VERSION 5.7 ;
  NOWIREEXTENSIONATPIN ON ;
  DIVIDERCHAR "/" ;
  BUSBITCHARS "[]" ;
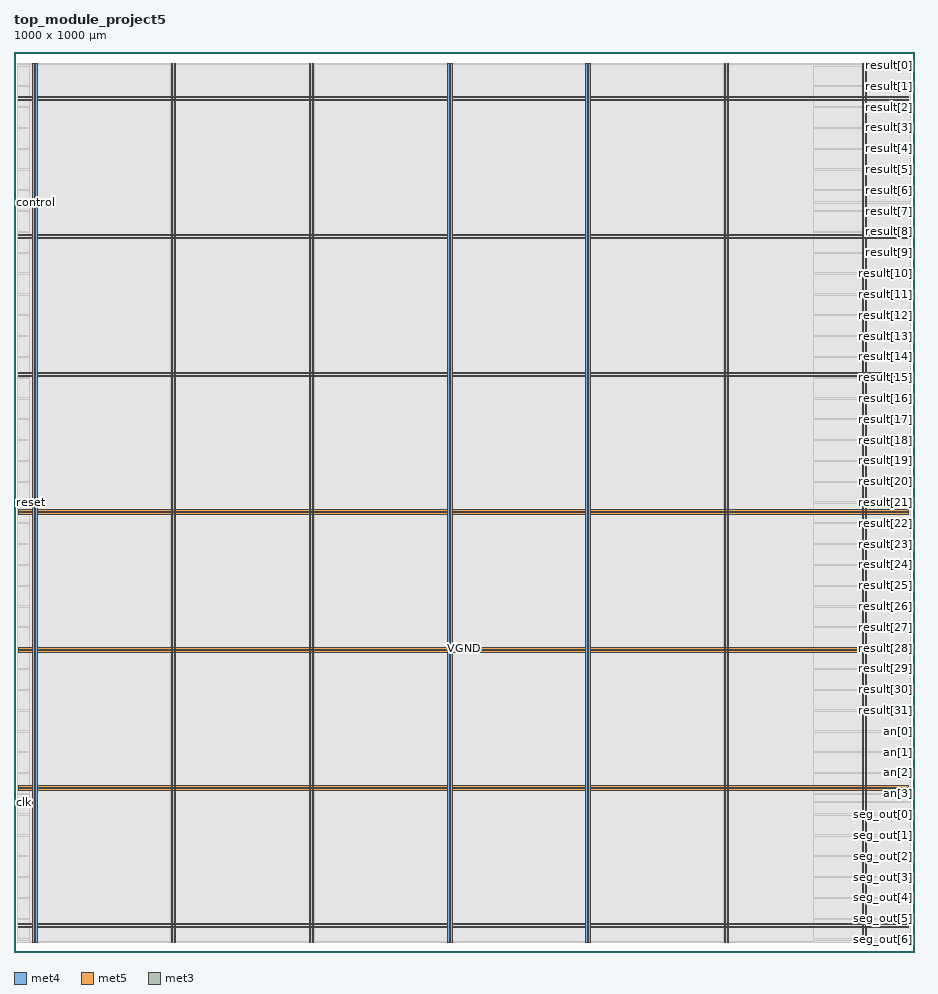
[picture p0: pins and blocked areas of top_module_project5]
MACRO top_module_project5
  CLASS BLOCK ;
  FOREIGN top_module_project5 ;
  ORIGIN 0.000 0.000 ;
  SIZE 1000.000 BY 1000.000 ;
  PIN VGND
    DIRECTION INOUT ;
    USE GROUND ;
    PORT
      LAYER met4 ;
        RECT 24.340 10.640 25.940 987.600 ;
    END
    PORT
      LAYER met4 ;
        RECT 177.940 10.640 179.540 987.600 ;
    END
    PORT
      LAYER met4 ;
        RECT 331.540 10.640 333.140 987.600 ;
    END
    PORT
      LAYER met4 ;
        RECT 485.140 10.640 486.740 987.600 ;
    END
    PORT
      LAYER met4 ;
        RECT 638.740 10.640 640.340 987.600 ;
    END
    PORT
      LAYER met4 ;
        RECT 792.340 10.640 793.940 987.600 ;
    END
    PORT
      LAYER met4 ;
        RECT 945.940 10.640 947.540 987.600 ;
    END
    PORT
      LAYER met5 ;
        RECT 5.280 30.030 994.300 31.630 ;
    END
    PORT
      LAYER met5 ;
        RECT 5.280 183.210 994.300 184.810 ;
    END
    PORT
      LAYER met5 ;
        RECT 5.280 336.390 994.300 337.990 ;
    END
    PORT
      LAYER met5 ;
        RECT 5.280 489.570 994.300 491.170 ;
    END
    PORT
      LAYER met5 ;
        RECT 5.280 642.750 994.300 644.350 ;
    END
    PORT
      LAYER met5 ;
        RECT 5.280 795.930 994.300 797.530 ;
    END
    PORT
      LAYER met5 ;
        RECT 5.280 949.110 994.300 950.710 ;
    END
  END VGND
  PIN VPWR
    DIRECTION INOUT ;
    USE POWER ;
    PORT
      LAYER met4 ;
        RECT 21.040 10.640 22.640 987.600 ;
    END
    PORT
      LAYER met4 ;
        RECT 174.640 10.640 176.240 987.600 ;
    END
    PORT
      LAYER met4 ;
        RECT 328.240 10.640 329.840 987.600 ;
    END
    PORT
      LAYER met4 ;
        RECT 481.840 10.640 483.440 987.600 ;
    END
    PORT
      LAYER met4 ;
        RECT 635.440 10.640 637.040 987.600 ;
    END
    PORT
      LAYER met4 ;
        RECT 789.040 10.640 790.640 987.600 ;
    END
    PORT
      LAYER met4 ;
        RECT 942.640 10.640 944.240 987.600 ;
    END
    PORT
      LAYER met5 ;
        RECT 5.280 26.730 994.300 28.330 ;
    END
    PORT
      LAYER met5 ;
        RECT 5.280 179.910 994.300 181.510 ;
    END
    PORT
      LAYER met5 ;
        RECT 5.280 333.090 994.300 334.690 ;
    END
    PORT
      LAYER met5 ;
        RECT 5.280 486.270 994.300 487.870 ;
    END
    PORT
      LAYER met5 ;
        RECT 5.280 639.450 994.300 641.050 ;
    END
    PORT
      LAYER met5 ;
        RECT 5.280 792.630 994.300 794.230 ;
    END
    PORT
      LAYER met5 ;
        RECT 5.280 945.810 994.300 947.410 ;
    END
  END VPWR
  PIN an[0]
    DIRECTION OUTPUT ;
    USE SIGNAL ;
    ANTENNADIFFAREA 0.445500 ;
    PORT
      LAYER met3 ;
        RECT 996.000 244.840 1000.000 245.440 ;
    END
  END an[0]
  PIN an[1]
    DIRECTION OUTPUT ;
    USE SIGNAL ;
    ANTENNADIFFAREA 0.445500 ;
    PORT
      LAYER met3 ;
        RECT 996.000 221.720 1000.000 222.320 ;
    END
  END an[1]
  PIN an[2]
    DIRECTION OUTPUT ;
    USE SIGNAL ;
    ANTENNADIFFAREA 0.445500 ;
    PORT
      LAYER met3 ;
        RECT 996.000 198.600 1000.000 199.200 ;
    END
  END an[2]
  PIN an[3]
    DIRECTION OUTPUT ;
    USE SIGNAL ;
    ANTENNADIFFAREA 0.445500 ;
    PORT
      LAYER met3 ;
        RECT 996.000 175.480 1000.000 176.080 ;
    END
  END an[3]
  PIN clk
    DIRECTION INPUT ;
    USE SIGNAL ;
    ANTENNAGATEAREA 0.852000 ;
    PORT
      LAYER met3 ;
        RECT 0.000 165.960 4.000 166.560 ;
    END
  END clk
  PIN control
    DIRECTION INPUT ;
    USE SIGNAL ;
    ANTENNAGATEAREA 0.990000 ;
    PORT
      LAYER met3 ;
        RECT 0.000 832.360 4.000 832.960 ;
    END
  END control
  PIN reset
    DIRECTION INPUT ;
    USE SIGNAL ;
    ANTENNAGATEAREA 0.742500 ;
    PORT
      LAYER met3 ;
        RECT 0.000 499.160 4.000 499.760 ;
    END
  END reset
  PIN result[0]
    DIRECTION OUTPUT ;
    USE SIGNAL ;
    ANTENNADIFFAREA 0.445500 ;
    PORT
      LAYER met3 ;
        RECT 996.000 984.680 1000.000 985.280 ;
    END
  END result[0]
  PIN result[10]
    DIRECTION OUTPUT ;
    USE SIGNAL ;
    ANTENNADIFFAREA 0.445500 ;
    PORT
      LAYER met3 ;
        RECT 996.000 753.480 1000.000 754.080 ;
    END
  END result[10]
  PIN result[11]
    DIRECTION OUTPUT ;
    USE SIGNAL ;
    ANTENNADIFFAREA 0.445500 ;
    PORT
      LAYER met3 ;
        RECT 996.000 730.360 1000.000 730.960 ;
    END
  END result[11]
  PIN result[12]
    DIRECTION OUTPUT ;
    USE SIGNAL ;
    ANTENNADIFFAREA 0.445500 ;
    PORT
      LAYER met3 ;
        RECT 996.000 707.240 1000.000 707.840 ;
    END
  END result[12]
  PIN result[13]
    DIRECTION OUTPUT ;
    USE SIGNAL ;
    ANTENNADIFFAREA 0.445500 ;
    PORT
      LAYER met3 ;
        RECT 996.000 684.120 1000.000 684.720 ;
    END
  END result[13]
  PIN result[14]
    DIRECTION OUTPUT ;
    USE SIGNAL ;
    ANTENNADIFFAREA 0.445500 ;
    PORT
      LAYER met3 ;
        RECT 996.000 661.000 1000.000 661.600 ;
    END
  END result[14]
  PIN result[15]
    DIRECTION OUTPUT ;
    USE SIGNAL ;
    ANTENNADIFFAREA 0.445500 ;
    PORT
      LAYER met3 ;
        RECT 996.000 637.880 1000.000 638.480 ;
    END
  END result[15]
  PIN result[16]
    DIRECTION OUTPUT ;
    USE SIGNAL ;
    ANTENNADIFFAREA 0.445500 ;
    PORT
      LAYER met3 ;
        RECT 996.000 614.760 1000.000 615.360 ;
    END
  END result[16]
  PIN result[17]
    DIRECTION OUTPUT ;
    USE SIGNAL ;
    ANTENNADIFFAREA 0.445500 ;
    PORT
      LAYER met3 ;
        RECT 996.000 591.640 1000.000 592.240 ;
    END
  END result[17]
  PIN result[18]
    DIRECTION OUTPUT ;
    USE SIGNAL ;
    ANTENNADIFFAREA 0.445500 ;
    PORT
      LAYER met3 ;
        RECT 996.000 568.520 1000.000 569.120 ;
    END
  END result[18]
  PIN result[19]
    DIRECTION OUTPUT ;
    USE SIGNAL ;
    ANTENNADIFFAREA 0.445500 ;
    PORT
      LAYER met3 ;
        RECT 996.000 545.400 1000.000 546.000 ;
    END
  END result[19]
  PIN result[1]
    DIRECTION OUTPUT ;
    USE SIGNAL ;
    ANTENNADIFFAREA 0.445500 ;
    PORT
      LAYER met3 ;
        RECT 996.000 961.560 1000.000 962.160 ;
    END
  END result[1]
  PIN result[20]
    DIRECTION OUTPUT ;
    USE SIGNAL ;
    ANTENNADIFFAREA 0.445500 ;
    PORT
      LAYER met3 ;
        RECT 996.000 522.280 1000.000 522.880 ;
    END
  END result[20]
  PIN result[21]
    DIRECTION OUTPUT ;
    USE SIGNAL ;
    ANTENNADIFFAREA 0.445500 ;
    PORT
      LAYER met3 ;
        RECT 996.000 499.160 1000.000 499.760 ;
    END
  END result[21]
  PIN result[22]
    DIRECTION OUTPUT ;
    USE SIGNAL ;
    ANTENNADIFFAREA 0.445500 ;
    PORT
      LAYER met3 ;
        RECT 996.000 476.040 1000.000 476.640 ;
    END
  END result[22]
  PIN result[23]
    DIRECTION OUTPUT ;
    USE SIGNAL ;
    ANTENNADIFFAREA 0.445500 ;
    PORT
      LAYER met3 ;
        RECT 996.000 452.920 1000.000 453.520 ;
    END
  END result[23]
  PIN result[24]
    DIRECTION OUTPUT ;
    USE SIGNAL ;
    ANTENNADIFFAREA 0.445500 ;
    PORT
      LAYER met3 ;
        RECT 996.000 429.800 1000.000 430.400 ;
    END
  END result[24]
  PIN result[25]
    DIRECTION OUTPUT ;
    USE SIGNAL ;
    ANTENNADIFFAREA 0.445500 ;
    PORT
      LAYER met3 ;
        RECT 996.000 406.680 1000.000 407.280 ;
    END
  END result[25]
  PIN result[26]
    DIRECTION OUTPUT ;
    USE SIGNAL ;
    ANTENNADIFFAREA 0.445500 ;
    PORT
      LAYER met3 ;
        RECT 996.000 383.560 1000.000 384.160 ;
    END
  END result[26]
  PIN result[27]
    DIRECTION OUTPUT ;
    USE SIGNAL ;
    ANTENNADIFFAREA 0.445500 ;
    PORT
      LAYER met3 ;
        RECT 996.000 360.440 1000.000 361.040 ;
    END
  END result[27]
  PIN result[28]
    DIRECTION OUTPUT ;
    USE SIGNAL ;
    ANTENNADIFFAREA 0.445500 ;
    PORT
      LAYER met3 ;
        RECT 996.000 337.320 1000.000 337.920 ;
    END
  END result[28]
  PIN result[29]
    DIRECTION OUTPUT ;
    USE SIGNAL ;
    ANTENNADIFFAREA 0.445500 ;
    PORT
      LAYER met3 ;
        RECT 996.000 314.200 1000.000 314.800 ;
    END
  END result[29]
  PIN result[2]
    DIRECTION OUTPUT ;
    USE SIGNAL ;
    ANTENNADIFFAREA 0.445500 ;
    PORT
      LAYER met3 ;
        RECT 996.000 938.440 1000.000 939.040 ;
    END
  END result[2]
  PIN result[30]
    DIRECTION OUTPUT ;
    USE SIGNAL ;
    ANTENNADIFFAREA 0.445500 ;
    PORT
      LAYER met3 ;
        RECT 996.000 291.080 1000.000 291.680 ;
    END
  END result[30]
  PIN result[31]
    DIRECTION OUTPUT ;
    USE SIGNAL ;
    ANTENNADIFFAREA 0.445500 ;
    PORT
      LAYER met3 ;
        RECT 996.000 267.960 1000.000 268.560 ;
    END
  END result[31]
  PIN result[3]
    DIRECTION OUTPUT ;
    USE SIGNAL ;
    ANTENNADIFFAREA 0.445500 ;
    PORT
      LAYER met3 ;
        RECT 996.000 915.320 1000.000 915.920 ;
    END
  END result[3]
  PIN result[4]
    DIRECTION OUTPUT ;
    USE SIGNAL ;
    ANTENNADIFFAREA 0.445500 ;
    PORT
      LAYER met3 ;
        RECT 996.000 892.200 1000.000 892.800 ;
    END
  END result[4]
  PIN result[5]
    DIRECTION OUTPUT ;
    USE SIGNAL ;
    ANTENNADIFFAREA 0.445500 ;
    PORT
      LAYER met3 ;
        RECT 996.000 869.080 1000.000 869.680 ;
    END
  END result[5]
  PIN result[6]
    DIRECTION OUTPUT ;
    USE SIGNAL ;
    ANTENNADIFFAREA 0.445500 ;
    PORT
      LAYER met3 ;
        RECT 996.000 845.960 1000.000 846.560 ;
    END
  END result[6]
  PIN result[7]
    DIRECTION OUTPUT ;
    USE SIGNAL ;
    ANTENNADIFFAREA 0.445500 ;
    PORT
      LAYER met3 ;
        RECT 996.000 822.840 1000.000 823.440 ;
    END
  END result[7]
  PIN result[8]
    DIRECTION OUTPUT ;
    USE SIGNAL ;
    ANTENNADIFFAREA 0.445500 ;
    PORT
      LAYER met3 ;
        RECT 996.000 799.720 1000.000 800.320 ;
    END
  END result[8]
  PIN result[9]
    DIRECTION OUTPUT ;
    USE SIGNAL ;
    ANTENNADIFFAREA 0.445500 ;
    PORT
      LAYER met3 ;
        RECT 996.000 776.600 1000.000 777.200 ;
    END
  END result[9]
  PIN seg_out[0]
    DIRECTION OUTPUT ;
    USE SIGNAL ;
    ANTENNADIFFAREA 0.445500 ;
    PORT
      LAYER met3 ;
        RECT 996.000 152.360 1000.000 152.960 ;
    END
  END seg_out[0]
  PIN seg_out[1]
    DIRECTION OUTPUT ;
    USE SIGNAL ;
    ANTENNADIFFAREA 0.445500 ;
    PORT
      LAYER met3 ;
        RECT 996.000 129.240 1000.000 129.840 ;
    END
  END seg_out[1]
  PIN seg_out[2]
    DIRECTION OUTPUT ;
    USE SIGNAL ;
    ANTENNADIFFAREA 0.445500 ;
    PORT
      LAYER met3 ;
        RECT 996.000 106.120 1000.000 106.720 ;
    END
  END seg_out[2]
  PIN seg_out[3]
    DIRECTION OUTPUT ;
    USE SIGNAL ;
    ANTENNADIFFAREA 0.445500 ;
    PORT
      LAYER met3 ;
        RECT 996.000 83.000 1000.000 83.600 ;
    END
  END seg_out[3]
  PIN seg_out[4]
    DIRECTION OUTPUT ;
    USE SIGNAL ;
    ANTENNADIFFAREA 0.445500 ;
    PORT
      LAYER met3 ;
        RECT 996.000 59.880 1000.000 60.480 ;
    END
  END seg_out[4]
  PIN seg_out[5]
    DIRECTION OUTPUT ;
    USE SIGNAL ;
    ANTENNADIFFAREA 0.445500 ;
    PORT
      LAYER met3 ;
        RECT 996.000 36.760 1000.000 37.360 ;
    END
  END seg_out[5]
  PIN seg_out[6]
    DIRECTION OUTPUT ;
    USE SIGNAL ;
    ANTENNADIFFAREA 0.445500 ;
    PORT
      LAYER met3 ;
        RECT 996.000 13.640 1000.000 14.240 ;
    END
  END seg_out[6]
  OBS
      LAYER nwell ;
        RECT 5.330 10.795 994.250 987.550 ;
      LAYER li1 ;
        RECT 5.520 10.795 994.060 987.445 ;
      LAYER met1 ;
        RECT 4.210 10.640 994.060 987.600 ;
      LAYER met2 ;
        RECT 4.230 10.695 992.130 987.545 ;
      LAYER met3 ;
        RECT 3.990 985.680 996.000 987.525 ;
        RECT 3.990 984.280 995.600 985.680 ;
        RECT 3.990 962.560 996.000 984.280 ;
        RECT 3.990 961.160 995.600 962.560 ;
        RECT 3.990 939.440 996.000 961.160 ;
        RECT 3.990 938.040 995.600 939.440 ;
        RECT 3.990 916.320 996.000 938.040 ;
        RECT 3.990 914.920 995.600 916.320 ;
        RECT 3.990 893.200 996.000 914.920 ;
        RECT 3.990 891.800 995.600 893.200 ;
        RECT 3.990 870.080 996.000 891.800 ;
        RECT 3.990 868.680 995.600 870.080 ;
        RECT 3.990 846.960 996.000 868.680 ;
        RECT 3.990 845.560 995.600 846.960 ;
        RECT 3.990 833.360 996.000 845.560 ;
        RECT 4.400 831.960 996.000 833.360 ;
        RECT 3.990 823.840 996.000 831.960 ;
        RECT 3.990 822.440 995.600 823.840 ;
        RECT 3.990 800.720 996.000 822.440 ;
        RECT 3.990 799.320 995.600 800.720 ;
        RECT 3.990 777.600 996.000 799.320 ;
        RECT 3.990 776.200 995.600 777.600 ;
        RECT 3.990 754.480 996.000 776.200 ;
        RECT 3.990 753.080 995.600 754.480 ;
        RECT 3.990 731.360 996.000 753.080 ;
        RECT 3.990 729.960 995.600 731.360 ;
        RECT 3.990 708.240 996.000 729.960 ;
        RECT 3.990 706.840 995.600 708.240 ;
        RECT 3.990 685.120 996.000 706.840 ;
        RECT 3.990 683.720 995.600 685.120 ;
        RECT 3.990 662.000 996.000 683.720 ;
        RECT 3.990 660.600 995.600 662.000 ;
        RECT 3.990 638.880 996.000 660.600 ;
        RECT 3.990 637.480 995.600 638.880 ;
        RECT 3.990 615.760 996.000 637.480 ;
        RECT 3.990 614.360 995.600 615.760 ;
        RECT 3.990 592.640 996.000 614.360 ;
        RECT 3.990 591.240 995.600 592.640 ;
        RECT 3.990 569.520 996.000 591.240 ;
        RECT 3.990 568.120 995.600 569.520 ;
        RECT 3.990 546.400 996.000 568.120 ;
        RECT 3.990 545.000 995.600 546.400 ;
        RECT 3.990 523.280 996.000 545.000 ;
        RECT 3.990 521.880 995.600 523.280 ;
        RECT 3.990 500.160 996.000 521.880 ;
        RECT 4.400 498.760 995.600 500.160 ;
        RECT 3.990 477.040 996.000 498.760 ;
        RECT 3.990 475.640 995.600 477.040 ;
        RECT 3.990 453.920 996.000 475.640 ;
        RECT 3.990 452.520 995.600 453.920 ;
        RECT 3.990 430.800 996.000 452.520 ;
        RECT 3.990 429.400 995.600 430.800 ;
        RECT 3.990 407.680 996.000 429.400 ;
        RECT 3.990 406.280 995.600 407.680 ;
        RECT 3.990 384.560 996.000 406.280 ;
        RECT 3.990 383.160 995.600 384.560 ;
        RECT 3.990 361.440 996.000 383.160 ;
        RECT 3.990 360.040 995.600 361.440 ;
        RECT 3.990 338.320 996.000 360.040 ;
        RECT 3.990 336.920 995.600 338.320 ;
        RECT 3.990 315.200 996.000 336.920 ;
        RECT 3.990 313.800 995.600 315.200 ;
        RECT 3.990 292.080 996.000 313.800 ;
        RECT 3.990 290.680 995.600 292.080 ;
        RECT 3.990 268.960 996.000 290.680 ;
        RECT 3.990 267.560 995.600 268.960 ;
        RECT 3.990 245.840 996.000 267.560 ;
        RECT 3.990 244.440 995.600 245.840 ;
        RECT 3.990 222.720 996.000 244.440 ;
        RECT 3.990 221.320 995.600 222.720 ;
        RECT 3.990 199.600 996.000 221.320 ;
        RECT 3.990 198.200 995.600 199.600 ;
        RECT 3.990 176.480 996.000 198.200 ;
        RECT 3.990 175.080 995.600 176.480 ;
        RECT 3.990 166.960 996.000 175.080 ;
        RECT 4.400 165.560 996.000 166.960 ;
        RECT 3.990 153.360 996.000 165.560 ;
        RECT 3.990 151.960 995.600 153.360 ;
        RECT 3.990 130.240 996.000 151.960 ;
        RECT 3.990 128.840 995.600 130.240 ;
        RECT 3.990 107.120 996.000 128.840 ;
        RECT 3.990 105.720 995.600 107.120 ;
        RECT 3.990 84.000 996.000 105.720 ;
        RECT 3.990 82.600 995.600 84.000 ;
        RECT 3.990 60.880 996.000 82.600 ;
        RECT 3.990 59.480 995.600 60.880 ;
        RECT 3.990 37.760 996.000 59.480 ;
        RECT 3.990 36.360 995.600 37.760 ;
        RECT 3.990 14.640 996.000 36.360 ;
        RECT 3.990 13.240 995.600 14.640 ;
        RECT 3.990 10.715 996.000 13.240 ;
      LAYER met4 ;
        RECT 16.855 11.735 20.640 985.825 ;
        RECT 23.040 11.735 23.940 985.825 ;
        RECT 26.340 11.735 174.240 985.825 ;
        RECT 176.640 11.735 177.540 985.825 ;
        RECT 179.940 11.735 327.840 985.825 ;
        RECT 330.240 11.735 331.140 985.825 ;
        RECT 333.540 11.735 481.440 985.825 ;
        RECT 483.840 11.735 484.740 985.825 ;
        RECT 487.140 11.735 635.040 985.825 ;
        RECT 637.440 11.735 638.340 985.825 ;
        RECT 640.740 11.735 788.640 985.825 ;
        RECT 791.040 11.735 791.940 985.825 ;
        RECT 794.340 11.735 888.425 985.825 ;
  END
END top_module_project5
END LIBRARY

